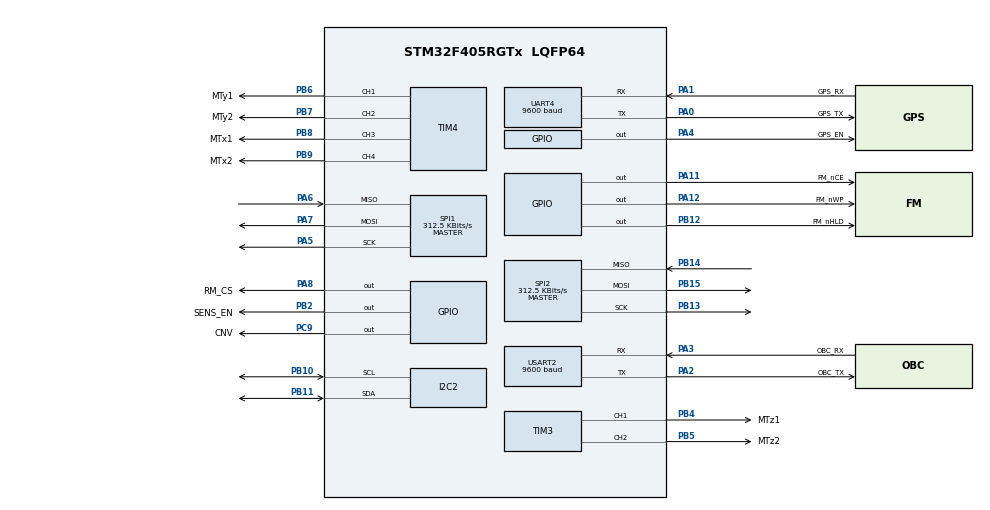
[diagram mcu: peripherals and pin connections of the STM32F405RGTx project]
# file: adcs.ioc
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Dma.Request0=USART2_TX
Dma.USART2_TX.0.Direction=DMA_MEMORY_TO_PERIPH
Dma.USART2_TX.0.FIFOMode=DMA_FIFOMODE_DISABLE
Dma.USART2_TX.0.Instance=DMA1_Stream6
Dma.USART2_TX.0.MemDataAlignment=DMA_MDATAALIGN_BYTE
Dma.USART2_TX.0.MemInc=DMA_MINC_ENABLE
Dma.USART2_TX.0.Mode=DMA_NORMAL
Dma.USART2_TX.0.PeriphDataAlignment=DMA_PDATAALIGN_BYTE
Dma.USART2_TX.0.PeriphInc=DMA_PINC_DISABLE
Dma.USART2_TX.0.Priority=DMA_PRIORITY_LOW
IWDG.Prescaler=IWDG_PRESCALER_256
IWDG.Reload=300
Mcu.Family=STM32F4
Mcu.Name=STM32F405RGTx
Mcu.Package=LQFP64
NVIC.DMA1_Stream6_IRQn=true\:0\:0\:false\:false\:true
NVIC.I2C2_EV_IRQn=true\:0\:0\:false\:false\:true
NVIC.PriorityGroup=NVIC_PRIORITYGROUP_4
NVIC.RTC_Alarm_IRQn=true\:0\:0\:false\:false\:true
NVIC.SPI1_IRQn=true\:0\:0\:false\:false\:true
NVIC.SPI2_IRQn=true\:0\:0\:false\:false\:true
NVIC.TIM7_IRQn=true\:0\:0\:false\:false\:true
NVIC.UART4_IRQn=true\:0\:0\:false\:false\:true
NVIC.USART2_IRQn=true\:0\:0\:false\:false\:true
PA0-WKUP.GPIO_Label=GPS_TX
PA0-WKUP.GPIO_Speed=GPIO_SPEED_FREQ_HIGH
PA0-WKUP.Mode=Asynchronous
PA0-WKUP.Signal=UART4_TX
PA1.GPIO_Label=GPS_RX
PA1.GPIO_Speed=GPIO_SPEED_FREQ_HIGH
PA1.Mode=Asynchronous
PA1.Signal=UART4_RX
PA11.GPIO_Label=FM_nCE
PA11.Signal=GPIO_Output
PA12.GPIO_Label=FM_nWP
PA12.Signal=GPIO_Output
PA13.Mode=Trace_Asynchronous_SW
PA13.Signal=SYS_JTMS-SWDIO
PA14.Mode=Trace_Asynchronous_SW
PA14.Signal=SYS_JTCK-SWCLK
PA2.GPIO_Label=OBC_TX
PA2.GPIO_Speed=GPIO_SPEED_FREQ_HIGH
PA2.Mode=Asynchronous
PA2.Signal=USART2_TX
PA3.GPIO_Label=OBC_RX
PA3.GPIO_Speed=GPIO_SPEED_FREQ_HIGH
PA3.Mode=Asynchronous
PA3.Signal=USART2_RX
PA4.GPIO_Label=GPS_EN
PA4.PinState=GPIO_PIN_SET
PA4.Signal=GPIO_Output
PA5.GPIO_Speed=GPIO_SPEED_FREQ_LOW
PA5.Mode=Full_Duplex_Master
PA5.Signal=SPI1_SCK
PA6.GPIO_Speed=GPIO_SPEED_FREQ_LOW
PA6.Mode=Full_Duplex_Master
PA6.Signal=SPI1_MISO
PA7.GPIO_Speed=GPIO_SPEED_FREQ_LOW
PA7.Mode=Full_Duplex_Master
PA7.Signal=SPI1_MOSI
PA8.GPIO_Label=RM_CS
PA8.Signal=GPIO_Output
PB10.GPIO_PuPdOD=GPIO_NOPULL
PB10.GPIO_Speed=GPIO_SPEED_FREQ_LOW
PB10.Mode=I2C
PB10.Signal=I2C2_SCL
PB11.GPIO_PuPdOD=GPIO_NOPULL
PB11.GPIO_Speed=GPIO_SPEED_FREQ_LOW
PB11.Mode=I2C
PB11.Signal=I2C2_SDA
PB12.GPIO_Label=FM_nHLD
PB12.Signal=GPIO_Output
PB13.GPIO_Speed=GPIO_SPEED_FREQ_LOW
PB13.Mode=Full_Duplex_Master
PB13.Signal=SPI2_SCK
PB14.GPIO_Speed=GPIO_SPEED_FREQ_LOW
PB14.Mode=Full_Duplex_Master
PB14.Signal=SPI2_MISO
PB15.GPIO_Speed=GPIO_SPEED_FREQ_LOW
PB15.Mode=Full_Duplex_Master
PB15.Signal=SPI2_MOSI
PB2.GPIO_Label=SENS_EN
PB2.PinState=GPIO_PIN_SET
PB2.Signal=GPIO_Output
PB3.Mode=Trace_Asynchronous_SW
PB3.Signal=SYS_JTDO-SWO
PB4.GPIO_Label=MTz1
PB4.Signal=S_TIM3_CH1
PB5.GPIO_Label=MTz2
PB5.Signal=S_TIM3_CH2
PB6.GPIO_Label=MTy1
PB6.Signal=S_TIM4_CH1
PB7.GPIO_Label=MTy2
PB7.Signal=S_TIM4_CH2
PB8.GPIO_Label=MTx1
PB8.Signal=S_TIM4_CH3
PB9.GPIO_Label=MTx2
PB9.Signal=S_TIM4_CH4
PC14-OSC32_IN.Mode=LSE-External-Oscillator
PC14-OSC32_IN.Signal=RCC_OSC32_IN
PC15-OSC32_OUT.Mode=LSE-External-Oscillator
PC15-OSC32_OUT.Signal=RCC_OSC32_OUT
PC9.GPIO_Label=CNV
PC9.Signal=GPIO_Output
PH0-OSC_IN.Mode=HSE-External-Oscillator
PH0-OSC_IN.Signal=RCC_OSC_IN
PH1-OSC_OUT.Mode=HSE-External-Oscillator
PH1-OSC_OUT.Signal=RCC_OSC_OUT
ProjectManager.HeapSize=0x200
ProjectManager.StackSize=0x400
ProjectManager.TargetToolchain=SW4STM32
RCC.48MHZClocksFreq_Value=22857142.85714286
RCC.AHBFreq_Value=80000000
RCC.APB1CLKDivider=RCC_HCLK_DIV2
RCC.APB1Freq_Value=40000000
RCC.APB1TimFreq_Value=80000000
RCC.APB2CLKDivider=RCC_HCLK_DIV2
RCC.APB2Freq_Value=40000000
RCC.APB2TimFreq_Value=80000000
RCC.CortexFreq_Value=80000000
RCC.HCLKFreq_Value=80000000
RCC.HSE_VALUE=12000000
RCC.HSI_VALUE=16000000
RCC.PLLM=6
RCC.PLLN=80
RCC.PLLQ=7
RCC.PLLSourceVirtual=RCC_PLLSOURCE_HSE
RCC.RCC_RTC_Clock_SourceVirtual=RCC_RTCCLKSOURCE_LSE
RCC.RCC_RTC_Clock_Source_FROM_HSE=RCC_RTCCLKSOURCE_HSE_DIV12
RCC.SYSCLKFreq_VALUE=80000000
RCC.SYSCLKSource=RCC_SYSCLKSOURCE_PLLCLK
RCC.VCOOutputFreq_Value=160000000
RTC.AlarmMask=RTC_ALARMMASK_DATEWEEKDAY
RTC.Format=RTC_FORMAT_BIN
SH.S_TIM3_CH1.0=TIM3_CH1,PWM Generation1 CH1
SH.S_TIM3_CH2.0=TIM3_CH2,PWM Generation2 CH2
SH.S_TIM4_CH1.0=TIM4_CH1,PWM Generation1 CH1
SH.S_TIM4_CH2.0=TIM4_CH2,PWM Generation2 CH2
SH.S_TIM4_CH3.0=TIM4_CH3,PWM Generation3 CH3
SH.S_TIM4_CH4.0=TIM4_CH4,PWM Generation4 CH4
SPI1.BaudRatePrescaler=SPI_BAUDRATEPRESCALER_128
SPI1.CalculateBaudRate=312.5 KBits/s
SPI1.Mode=SPI_MODE_MASTER
SPI2.BaudRatePrescaler=SPI_BAUDRATEPRESCALER_128
SPI2.CalculateBaudRate=312.5 KBits/s
SPI2.Mode=SPI_MODE_MASTER
TIM3.Channel-PWM\ Generation2\ CH2=TIM_CHANNEL_2
TIM4.Channel-PWM\ Generation2\ CH2=TIM_CHANNEL_2
TIM4.Channel-PWM\ Generation3\ CH3=TIM_CHANNEL_3
TIM4.Channel-PWM\ Generation4\ CH4=TIM_CHANNEL_4
TIM7.Period=50000
TIM7.Prescaler=2048
UART4.BaudRate=9600
USART2.BaudRate=9600
VP_CRC_VS_CRC.Mode=CRC_Activate
VP_IWDG_VS_IWDG.Mode=IWDG_Activate
VP_RTC_VS_RTC_Alarm_A_Intern.Mode=Alarm A
VP_TIM7_VS_ClockSourceINT.Mode=Enable_Timer
board=adcs

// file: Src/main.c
/**
 ******************************************************************************
 * File Name          : main.c
 * Description        : Main program body
 ******************************************************************************
 *
 * COPYRIGHT(c) 2016 STMicroelectronics
 *
 * Redistribution and use in source and binary forms, with or without modification,
 * are permitted provided that the following conditions are met:
 *   1. Redistributions of source code must retain the above copyright notice,
 *      this list of conditions and the following disclaimer.
 *   2. Redistributions in binary form must reproduce the above copyright notice,
 *      this list of conditions and the following disclaimer in the documentation
 *      and/or other materials provided with the distribution.
 *   3. Neither the name of STMicroelectronics nor the names of its contributors
 *      may be used to endorse or promote products derived from this software
 *      without specific prior written permission.
 *
 * THIS SOFTWARE IS PROVIDED BY THE COPYRIGHT HOLDERS AND CONTRIBUTORS "AS IS"
 * AND ANY EXPRESS OR IMPLIED WARRANTIES, INCLUDING, BUT NOT LIMITED TO, THE
 * IMPLIED WARRANTIES OF MERCHANTABILITY AND FITNESS FOR A PARTICULAR PURPOSE ARE
 * DISCLAIMED. IN NO EVENT SHALL THE COPYRIGHT HOLDER OR CONTRIBUTORS BE LIABLE
 * FOR ANY DIRECT, INDIRECT, INCIDENTAL, SPECIAL, EXEMPLARY, OR CONSEQUENTIAL
 * DAMAGES (INCLUDING, BUT NOT LIMITED TO, PROCUREMENT OF SUBSTITUTE GOODS OR
 * SERVICES; LOSS OF USE, DATA, OR PROFITS; OR BUSINESS INTERRUPTION) HOWEVER
 * CAUSED AND ON ANY THEORY OF LIABILITY, WHETHER IN CONTRACT, STRICT LIABILITY,
 * OR TORT (INCLUDING NEGLIGENCE OR OTHERWISE) ARISING IN ANY WAY OUT OF THE USE
 * OF THIS SOFTWARE, EVEN IF ADVISED OF THE POSSIBILITY OF SUCH DAMAGE.
 *
 ******************************************************************************
 */
#include "stm32f4xx_hal.h"

/* USER CODE BEGIN Includes */

#include "adcs_manager.h"

#include "sysview.h"

/* USER CODE END Includes */

CRC_HandleTypeDef hcrc;

I2C_HandleTypeDef hi2c2;

IWDG_HandleTypeDef hiwdg;

RTC_HandleTypeDef hrtc;

SPI_HandleTypeDef hspi1;
SPI_HandleTypeDef hspi2;

TIM_HandleTypeDef htim3;
TIM_HandleTypeDef htim4;
TIM_HandleTypeDef htim7;

UART_HandleTypeDef huart4;
UART_HandleTypeDef huart2;
DMA_HandleTypeDef hdma_usart2_tx;

/* USER CODE BEGIN PV */
/* Private variables ---------------------------------------------------------*/

/* USER CODE END PV */

void SystemClock_Config(void);
void Error_Handler(void);
static void MX_GPIO_Init(void);
static void MX_DMA_Init(void);
static void MX_I2C2_Init(void);
static void MX_SPI1_Init(void);
static void MX_SPI2_Init(void);
static void MX_TIM3_Init(void);
static void MX_TIM4_Init(void);
static void MX_UART4_Init(void);
static void MX_USART2_UART_Init(void);
static void MX_TIM7_Init(void);
static void MX_CRC_Init(void);
static void MX_IWDG_Init(void);
static void MX_RTC_Init(void);

void HAL_TIM_MspPostInit(TIM_HandleTypeDef *htim);

/* USER CODE BEGIN PFP */
/* Private function prototypes -----------------------------------------------*/

void adcs_sysview_print();

/* USER CODE END PFP */

int main(void) {

    /* USER CODE BEGIN 1 */

    uint32_t obc_request_time = 0;

    /* Reset error status */
    error_status = ERROR_OK;

    /* USER CODE END 1 */

    /* MCU Configuration----------------------------------------------------------*/

    /* Reset of all peripherals, Initializes the Flash interface and the Systick. */
    HAL_Init();

    /* Wait for EPS ready */
    HAL_Delay(EPS_DELAY_READY);

    /* Configure the system clock */
    SystemClock_Config();

    /* Initialize all configured peripherals */
    MX_GPIO_Init();
    MX_DMA_Init();
    MX_I2C2_Init();
    MX_SPI1_Init();
    MX_SPI2_Init();
    MX_TIM3_Init();
    MX_TIM4_Init();
    MX_UART4_Init();
    MX_USART2_UART_Init();
    MX_TIM7_Init();
    MX_CRC_Init();
    MX_IWDG_Init();
    MX_RTC_Init();

    /* USER CODE BEGIN 2 */

    SEGGER_SYSVIEW_Conf();
    sysview_init();

    HAL_IWDG_Refresh(&hiwdg);

    error_status = init_mem();
    error_status = increment_boot_counter();
    error_status = init_obc_communication(adcs_boot_cnt);

    get_time_UTC(&adcs_time.utc);
    error_status = init_gps(adcs_time.utc, &gps_state);
    error_status = init_tle();

    HAL_IWDG_Refresh(&hiwdg);

    error_status = init_actuators();
    error_status = init_measured_vectors();
    error_status = init_attitude_determination();

    /* Kick timer interrupt for timed threads */
    if (kick_TIM7_timed_interrupt(LOOP_TIME_TICKS) == HAL_ERROR) {
        ADCS_event_period_status = TIMED_EVENT_NOT_SERVICED;
    }
    HAL_IWDG_Refresh(&hiwdg);
    /* USER CODE END 2 */

    /**************************************/
//    adcs_time.utc.year = 16;
//    adcs_time.utc.month = 8;
//    adcs_time.utc.day = 8;
//    adcs_time.utc.weekday = RTC_WEEKDAY_MONDAY;
//    adcs_time.utc.hour = 20;
//    adcs_time.utc.min = 30;
//    adcs_time.utc.sec = 0;
//    set_time_UTC(adcs_time.utc);
//
//    int16_t XM[3000];
//    int32_t RM[3000];
//    uint16_t j = 0;
    /**************************************/

    /* Infinite loop */
    /* USER CODE BEGIN WHILE */
    while (1) {
        /* GPS update */
        error_status = update_gps(&gps_state);

        /* Control loop runs at 68ms, interrupt runs every ~1.2s, WDG at ~2.4s */
        if (ADCS_event_period_status == TIMED_EVENT_NOT_SERVICED) {
            /* Send to EPS a packet */
            update_eps_pkt();
            /* Close Magneto-torquer for ms */
            magneto_torquer_off();
            /* Update measured vectors */
            error_status = update_measured_vectors();
            /**************************************/
//                    if (j<3000) {
//                        RM[j] = adcs_sensors.mgn.rm_raw[0];
//                        XM[j] = adcs_sensors.imu.xm_raw[0];
//                        j++;
//                        RM[j] = adcs_sensors.mgn.rm_raw[1];
//                        XM[j] = adcs_sensors.imu.xm_raw[1];
//                        j++;
//                        RM[j] = adcs_sensors.mgn.rm_raw[2];
//                        XM[j] = adcs_sensors.imu.xm_raw[2];
//                        j++;
//
//                    } else {
//                        break;
//                    }
            /**************************************/
            /* Open Magneto-torquer with previous current values */
            magneto_torquer_on();
            /* Get time for RTC*/
            get_time_UTC(&adcs_time.utc);
            /* Check if time is correct */
            if (adcs_time.utc.year > 15) {
                /* When set time with OBC RTC update GPS_ALARM only in the first time*/
                if (adcs_time.set_time == false) {
                    update_gps_alarm_from_flash(adcs_time.utc, &gps_state);
                    obc_request_time = 0;
                    adcs_time.set_time = true;
                }
                /* Calculate decimal year and Julian day */
                error_status = time_converter();
                /* Check if the SGP4 is correct */
                if (update_sgp4() == ERROR_OK) {
                    /* Update reference vectors */
                    error_status = update_reference_vectors();
                    /* Calculate Euler angles and angular velocities */
                    error_status = update_attitude_determination();
                } else {
                    error_status = ERROR_SGP4;
                }
            } else {
                /* Time isn't set by OBC, request time every ~11sec */
                error_status = ERROR_TIME;
                adcs_time.set_time = false;
                uint32_t obc_request_get_tick = HAL_sys_GetTick();
                if (obc_request_get_tick - obc_request_time> OBC_REQUEST_TIME_UPDATE) {
                    time_management_request_time_in_utc(OBC_APP_ID);
                    obc_request_time = obc_request_get_tick;
                }
            }
            /* Calculate control signals */
            error_status = attitude_control();
            /* Set actuators according to control signals */
            error_status = update_actuators();
            /* Update flag */
            ADCS_event_period_status = TIMED_EVENT_SERVICED;
            /* Software error handler runs for actuator and sensor 230ms*/
            adcs_sysview_print();
            error_handler(error_status);
            error_status = ERROR_OK;
        }

        error_status = update_obc_communication();

        /* USER CODE END WHILE */

    }

}

/** System Clock Configuration
 */
void SystemClock_Config(void) {

    RCC_OscInitTypeDef RCC_OscInitStruct;
    RCC_ClkInitTypeDef RCC_ClkInitStruct;
    RCC_PeriphCLKInitTypeDef PeriphClkInitStruct;

    __HAL_RCC_PWR_CLK_ENABLE();

    __HAL_PWR_VOLTAGESCALING_CONFIG(PWR_REGULATOR_VOLTAGE_SCALE1);

    RCC_OscInitStruct.OscillatorType = RCC_OSCILLATORTYPE_LSI
            | RCC_OSCILLATORTYPE_HSE | RCC_OSCILLATORTYPE_LSE;
    RCC_OscInitStruct.HSEState = RCC_HSE_ON;
    RCC_OscInitStruct.LSEState = RCC_LSE_ON;
    RCC_OscInitStruct.LSIState = RCC_LSI_ON;
    RCC_OscInitStruct.PLL.PLLState = RCC_PLL_ON;
    RCC_OscInitStruct.PLL.PLLSource = RCC_PLLSOURCE_HSE;
    RCC_OscInitStruct.PLL.PLLM = 6;
    RCC_OscInitStruct.PLL.PLLN = 168;
    RCC_OscInitStruct.PLL.PLLP = RCC_PLLP_DIV2;
    RCC_OscInitStruct.PLL.PLLQ = 7;
    if (HAL_RCC_OscConfig(&RCC_OscInitStruct) != HAL_OK) {
        Error_Handler();
    }

    RCC_ClkInitStruct.ClockType = RCC_CLOCKTYPE_HCLK | RCC_CLOCKTYPE_SYSCLK
            | RCC_CLOCKTYPE_PCLK1 | RCC_CLOCKTYPE_PCLK2;
    RCC_ClkInitStruct.SYSCLKSource = RCC_SYSCLKSOURCE_PLLCLK;
    RCC_ClkInitStruct.AHBCLKDivider = RCC_SYSCLK_DIV1;
    RCC_ClkInitStruct.APB1CLKDivider = RCC_HCLK_DIV4;
    RCC_ClkInitStruct.APB2CLKDivider = RCC_HCLK_DIV2;
    if (HAL_RCC_ClockConfig(&RCC_ClkInitStruct, FLASH_LATENCY_5) != HAL_OK) {
        Error_Handler();
    }

    PeriphClkInitStruct.PeriphClockSelection = RCC_PERIPHCLK_RTC;
    PeriphClkInitStruct.RTCClockSelection = RCC_RTCCLKSOURCE_LSE;
    if (HAL_RCCEx_PeriphCLKConfig(&PeriphClkInitStruct) != HAL_OK) {
        Error_Handler();
    }

    HAL_SYSTICK_Config(HAL_RCC_GetHCLKFreq() / 1000);

    HAL_SYSTICK_CLKSourceConfig(SYSTICK_CLKSOURCE_HCLK);

    /* SysTick_IRQn interrupt configuration */
    HAL_NVIC_SetPriority(SysTick_IRQn, 0, 0);
}

/* CRC init function */
static void MX_CRC_Init(void) {

    hcrc.Instance = CRC;
    if (HAL_CRC_Init(&hcrc) != HAL_OK) {
        Error_Handler();
    }

}

/* I2C2 init function */
static void MX_I2C2_Init(void) {

    hi2c2.Instance = I2C2;
    hi2c2.Init.ClockSpeed = 100000;
    hi2c2.Init.DutyCycle = I2C_DUTYCYCLE_2;
    hi2c2.Init.OwnAddress1 = 0;
    hi2c2.Init.AddressingMode = I2C_ADDRESSINGMODE_7BIT;
    hi2c2.Init.DualAddressMode = I2C_DUALADDRESS_DISABLE;
    hi2c2.Init.OwnAddress2 = 0;
    hi2c2.Init.GeneralCallMode = I2C_GENERALCALL_DISABLE;
    hi2c2.Init.NoStretchMode = I2C_NOSTRETCH_ENABLE;
    if (HAL_I2C_Init(&hi2c2) != HAL_OK) {
        Error_Handler();
    }

}

/* IWDG init function */
static void MX_IWDG_Init(void) {

    hiwdg.Instance = IWDG;
    hiwdg.Init.Prescaler = IWDG_PRESCALER_256;
    hiwdg.Init.Reload = 300;
    if (HAL_IWDG_Init(&hiwdg) != HAL_OK) {
        Error_Handler();
    }

}

/* RTC init function */
static void MX_RTC_Init(void) {

    RTC_TimeTypeDef sTime;
    RTC_DateTypeDef sDate;
    RTC_AlarmTypeDef sAlarm;

    /**Initialize RTC and set the Time and Date
     */
    hrtc.Instance = RTC;
    hrtc.Init.HourFormat = RTC_HOURFORMAT_24;
    hrtc.Init.AsynchPrediv = 127;
    hrtc.Init.SynchPrediv = 255;
    hrtc.Init.OutPut = RTC_OUTPUT_DISABLE;
    hrtc.Init.OutPutPolarity = RTC_OUTPUT_POLARITY_HIGH;
    hrtc.Init.OutPutType = RTC_OUTPUT_TYPE_OPENDRAIN;
    if (HAL_RTC_Init(&hrtc) != HAL_OK) {
        Error_Handler();
    }

    sTime.Hours = 0;
    sTime.Minutes = 0;
    sTime.Seconds = 0;
    sTime.DayLightSaving = RTC_DAYLIGHTSAVING_NONE;
    sTime.StoreOperation = RTC_STOREOPERATION_RESET;
    if (HAL_RTC_SetTime(&hrtc, &sTime, RTC_FORMAT_BIN) != HAL_OK) {
        Error_Handler();
    }

    sDate.WeekDay = RTC_WEEKDAY_MONDAY;
    sDate.Month = RTC_MONTH_JANUARY;
    sDate.Date = 1;
    sDate.Year = 0;

    if (HAL_RTC_SetDate(&hrtc, &sDate, RTC_FORMAT_BIN) != HAL_OK) {
        Error_Handler();
    }

    /**Enable the Alarm A
     */
    sAlarm.AlarmTime.Hours = 0;
    sAlarm.AlarmTime.Minutes = 0;
    sAlarm.AlarmTime.Seconds = 0;
    sAlarm.AlarmTime.SubSeconds = 0;
    sAlarm.AlarmTime.DayLightSaving = RTC_DAYLIGHTSAVING_NONE;
    sAlarm.AlarmTime.StoreOperation = RTC_STOREOPERATION_RESET;
    sAlarm.AlarmMask = RTC_ALARMMASK_DATEWEEKDAY;
    sAlarm.AlarmSubSecondMask = RTC_ALARMSUBSECONDMASK_ALL;
    sAlarm.AlarmDateWeekDaySel = RTC_ALARMDATEWEEKDAYSEL_DATE;
    sAlarm.AlarmDateWeekDay = 1;
    sAlarm.Alarm = RTC_ALARM_A;
    if (HAL_RTC_SetAlarm_IT(&hrtc, &sAlarm, RTC_FORMAT_BIN) != HAL_OK) {
        Error_Handler();
    }

}

/* SPI1 init function */
static void MX_SPI1_Init(void) {

    hspi1.Instance = SPI1;
    hspi1.Init.Mode = SPI_MODE_MASTER;
    hspi1.Init.Direction = SPI_DIRECTION_2LINES;
    hspi1.Init.DataSize = SPI_DATASIZE_8BIT;
    hspi1.Init.CLKPolarity = SPI_POLARITY_LOW;
    hspi1.Init.CLKPhase = SPI_PHASE_1EDGE;
    hspi1.Init.NSS = SPI_NSS_SOFT;
    hspi1.Init.BaudRatePrescaler = SPI_BAUDRATEPRESCALER_256;
    hspi1.Init.FirstBit = SPI_FIRSTBIT_MSB;
    hspi1.Init.TIMode = SPI_TIMODE_DISABLE;
    hspi1.Init.CRCCalculation = SPI_CRCCALCULATION_DISABLE;
    hspi1.Init.CRCPolynomial = 10;
    if (HAL_SPI_Init(&hspi1) != HAL_OK) {
        Error_Handler();
    }

}

/* SPI2 init function */
static void MX_SPI2_Init(void) {

    hspi2.Instance = SPI2;
    hspi2.Init.Mode = SPI_MODE_MASTER;
    hspi2.Init.Direction = SPI_DIRECTION_2LINES;
    hspi2.Init.DataSize = SPI_DATASIZE_8BIT;
    hspi2.Init.CLKPolarity = SPI_POLARITY_LOW;
    hspi2.Init.CLKPhase = SPI_PHASE_1EDGE;
    hspi2.Init.NSS = SPI_NSS_SOFT;
    hspi2.Init.BaudRatePrescaler = SPI_BAUDRATEPRESCALER_128;
    hspi2.Init.FirstBit = SPI_FIRSTBIT_MSB;
    hspi2.Init.TIMode = SPI_TIMODE_DISABLE;
    hspi2.Init.CRCCalculation = SPI_CRCCALCULATION_DISABLE;
    hspi2.Init.CRCPolynomial = 10;
    if (HAL_SPI_Init(&hspi2) != HAL_OK) {
        Error_Handler();
    }

}

/* TIM3 init function */
static void MX_TIM3_Init(void) {

    TIM_MasterConfigTypeDef sMasterConfig;
    TIM_OC_InitTypeDef sConfigOC;

    htim3.Instance = TIM3;
    htim3.Init.Prescaler = 0;
    htim3.Init.CounterMode = TIM_COUNTERMODE_UP;
    htim3.Init.Period = 0;
    htim3.Init.ClockDivision = TIM_CLOCKDIVISION_DIV1;
    if (HAL_TIM_PWM_Init(&htim3) != HAL_OK) {
        Error_Handler();
    }

    sMasterConfig.MasterOutputTrigger = TIM_TRGO_RESET;
    sMasterConfig.MasterSlaveMode = TIM_MASTERSLAVEMODE_DISABLE;
    if (HAL_TIMEx_MasterConfigSynchronization(&htim3, &sMasterConfig)
            != HAL_OK) {
        Error_Handler();
    }

    sConfigOC.OCMode = TIM_OCMODE_PWM1;
    sConfigOC.Pulse = 0;
    sConfigOC.OCPolarity = TIM_OCPOLARITY_HIGH;
    sConfigOC.OCFastMode = TIM_OCFAST_DISABLE;
    if (HAL_TIM_PWM_ConfigChannel(&htim3, &sConfigOC, TIM_CHANNEL_1)
            != HAL_OK) {
        Error_Handler();
    }

    if (HAL_TIM_PWM_ConfigChannel(&htim3, &sConfigOC, TIM_CHANNEL_2)
            != HAL_OK) {
        Error_Handler();
    }

    HAL_TIM_MspPostInit(&htim3);

}

/* TIM4 init function */
static void MX_TIM4_Init(void) {

    TIM_MasterConfigTypeDef sMasterConfig;
    TIM_OC_InitTypeDef sConfigOC;

    htim4.Instance = TIM4;
    htim4.Init.Prescaler = 0;
    htim4.Init.CounterMode = TIM_COUNTERMODE_UP;
    htim4.Init.Period = 0;
    htim4.Init.ClockDivision = TIM_CLOCKDIVISION_DIV1;
    if (HAL_TIM_PWM_Init(&htim4) != HAL_OK) {
        Error_Handler();
    }

    sMasterConfig.MasterOutputTrigger = TIM_TRGO_RESET;
    sMasterConfig.MasterSlaveMode = TIM_MASTERSLAVEMODE_DISABLE;
    if (HAL_TIMEx_MasterConfigSynchronization(&htim4, &sMasterConfig)
            != HAL_OK) {
        Error_Handler();
    }

    sConfigOC.OCMode = TIM_OCMODE_PWM1;
    sConfigOC.Pulse = 0;
    sConfigOC.OCPolarity = TIM_OCPOLARITY_HIGH;
    sConfigOC.OCFastMode = TIM_OCFAST_DISABLE;
    if (HAL_TIM_PWM_ConfigChannel(&htim4, &sConfigOC, TIM_CHANNEL_1)
            != HAL_OK) {
        Error_Handler();
    }

    if (HAL_TIM_PWM_ConfigChannel(&htim4, &sConfigOC, TIM_CHANNEL_2)
            != HAL_OK) {
        Error_Handler();
    }

    if (HAL_TIM_PWM_ConfigChannel(&htim4, &sConfigOC, TIM_CHANNEL_3)
            != HAL_OK) {
        Error_Handler();
    }

    if (HAL_TIM_PWM_ConfigChannel(&htim4, &sConfigOC, TIM_CHANNEL_4)
            != HAL_OK) {
        Error_Handler();
    }

    HAL_TIM_MspPostInit(&htim4);

}

/* TIM7 init function */
static void MX_TIM7_Init(void) {

    TIM_MasterConfigTypeDef sMasterConfig;

    htim7.Instance = TIM7;
    htim7.Init.Prescaler = 2048;
    htim7.Init.CounterMode = TIM_COUNTERMODE_UP;
    htim7.Init.Period = 50000;
    if (HAL_TIM_Base_Init(&htim7) != HAL_OK) {
        Error_Handler();
    }

    sMasterConfig.MasterOutputTrigger = TIM_TRGO_RESET;
    sMasterConfig.MasterSlaveMode = TIM_MASTERSLAVEMODE_DISABLE;
    if (HAL_TIMEx_MasterConfigSynchronization(&htim7, &sMasterConfig)
            != HAL_OK) {
        Error_Handler();
    }

}

/* UART4 init function */
static void MX_UART4_Init(void) {

    huart4.Instance = UART4;
    huart4.Init.BaudRate = 9600;
    huart4.Init.WordLength = UART_WORDLENGTH_8B;
    huart4.Init.StopBits = UART_STOPBITS_1;
    huart4.Init.Parity = UART_PARITY_NONE;
    huart4.Init.Mode = UART_MODE_TX_RX;
    huart4.Init.HwFlowCtl = UART_HWCONTROL_NONE;
    huart4.Init.OverSampling = UART_OVERSAMPLING_16;
    if (HAL_UART_Init(&huart4) != HAL_OK) {
        Error_Handler();
    }

}

/* USART2 init function */
static void MX_USART2_UART_Init(void) {

    huart2.Instance = USART2;
    huart2.Init.BaudRate = 9600;
    huart2.Init.WordLength = UART_WORDLENGTH_8B;
    huart2.Init.StopBits = UART_STOPBITS_1;
    huart2.Init.Parity = UART_PARITY_NONE;
    huart2.Init.Mode = UART_MODE_TX_RX;
    huart2.Init.HwFlowCtl = UART_HWCONTROL_NONE;
    huart2.Init.OverSampling = UART_OVERSAMPLING_16;
    if (HAL_UART_Init(&huart2) != HAL_OK) {
        Error_Handler();
    }

}

static void MX_DMA_Init(void) {
    /* DMA controller clock enable */
    __HAL_RCC_DMA1_CLK_ENABLE();

    /* DMA interrupt init */
    /* DMA1_Stream6_IRQn interrupt configuration */
    HAL_NVIC_SetPriority(DMA1_Stream6_IRQn, 0, 0);
    HAL_NVIC_EnableIRQ(DMA1_Stream6_IRQn);

}

/** Configure pins as
 * Analog
 * Input
 * Output
 * EVENT_OUT
 * EXTI
 */
static void MX_GPIO_Init(void) {

    GPIO_InitTypeDef GPIO_InitStruct;

    /* GPIO Ports Clock Enable */
    __HAL_RCC_GPIOC_CLK_ENABLE();
    __HAL_RCC_GPIOH_CLK_ENABLE();
    __HAL_RCC_GPIOA_CLK_ENABLE();
    __HAL_RCC_GPIOB_CLK_ENABLE();

    /*Configure GPIO pin Output Level */
    HAL_GPIO_WritePin(GPS_EN_GPIO_Port, GPS_EN_Pin, GPIO_PIN_SET);

    /*Configure GPIO pin Output Level */
    HAL_GPIO_WritePin(SENS_EN_GPIO_Port, SENS_EN_Pin, GPIO_PIN_SET);

    /*Configure GPIO pin Output Level */
    HAL_GPIO_WritePin(FM_nHLD_GPIO_Port, FM_nHLD_Pin, GPIO_PIN_RESET);

    /*Configure GPIO pin Output Level */
    HAL_GPIO_WritePin(CNV_GPIO_Port, CNV_Pin, GPIO_PIN_RESET);

    /*Configure GPIO pin Output Level */
    HAL_GPIO_WritePin(GPIOA, RM_CS_Pin | FM_nCE_Pin | FM_nWP_Pin,
            GPIO_PIN_RESET);

    /*Configure GPIO pins : GPS_EN_Pin RM_CS_Pin FM_nCE_Pin FM_nWP_Pin */
    GPIO_InitStruct.Pin = GPS_EN_Pin | RM_CS_Pin | FM_nCE_Pin | FM_nWP_Pin;
    GPIO_InitStruct.Mode = GPIO_MODE_OUTPUT_PP;
    GPIO_InitStruct.Pull = GPIO_NOPULL;
    GPIO_InitStruct.Speed = GPIO_SPEED_FREQ_LOW;
    HAL_GPIO_Init(GPIOA, &GPIO_InitStruct);

    /*Configure GPIO pins : SENS_EN_Pin FM_nHLD_Pin */
    GPIO_InitStruct.Pin = SENS_EN_Pin | FM_nHLD_Pin;
    GPIO_InitStruct.Mode = GPIO_MODE_OUTPUT_PP;
    GPIO_InitStruct.Pull = GPIO_NOPULL;
    GPIO_InitStruct.Speed = GPIO_SPEED_FREQ_LOW;
    HAL_GPIO_Init(GPIOB, &GPIO_InitStruct);

    /*Configure GPIO pin : CNV_Pin */
    GPIO_InitStruct.Pin = CNV_Pin;
    GPIO_InitStruct.Mode = GPIO_MODE_OUTPUT_PP;
    GPIO_InitStruct.Pull = GPIO_NOPULL;
    GPIO_InitStruct.Speed = GPIO_SPEED_FREQ_LOW;
    HAL_GPIO_Init(CNV_GPIO_Port, &GPIO_InitStruct);

}

/* USER CODE BEGIN 4 */

void adcs_sysview_print() {
    SYSVIEW_PRINT("BOOT COUNTER %ld", adcs_boot_cnt);
    SYSVIEW_PRINT("ERROR STATUS %d", error_status);
    SYSVIEW_PRINT("GPS STATUS %d", gps_state.status);
    SYSVIEW_PRINT("EULER %.2f %.2f %.2f", DEG(WahbaRot.Euler[0]),
            DEG(WahbaRot.Euler[1]), DEG(WahbaRot.Euler[2]));
    SYSVIEW_PRINT("W %.2f %.2f %.2f", DEG(WahbaRot.W[0]), DEG(WahbaRot.W[1]),
            DEG(WahbaRot.W[2]));
    SYSVIEW_PRINT("TEMPERATURE %.2f", adcs_sensors.temp.temp_c);
    SYSVIEW_PRINT("IGRF %.2f %.2f %.2f %.2f", igrf_vector.Xm,
            igrf_vector.Ym, igrf_vector.Zm, igrf_vector.norm);
    SYSVIEW_PRINT("RM %.2f %.2f %.2f %.2f", adcs_sensors.mgn.rm_f[0],
            adcs_sensors.mgn.rm_f[1], adcs_sensors.mgn.rm_f[2], adcs_sensors.mgn.rm_norm);
    SYSVIEW_PRINT("XM %.2f %.2f %.2f %.2f", adcs_sensors.imu.xm_f[0],
            adcs_sensors.imu.xm_f[1], adcs_sensors.imu.xm_f[2], adcs_sensors.imu.xm_norm);
    SYSVIEW_PRINT("GYRO %.2f %.2f %.2f", DEG(adcs_sensors.imu.gyr_f[0]),
            DEG(adcs_sensors.imu.gyr_f[1]), DEG(adcs_sensors.imu.gyr_f[2]));
    SYSVIEW_PRINT("GYRO %d %d %d", adcs_sensors.imu.gyr_raw[0],
            adcs_sensors.imu.gyr_raw[1], adcs_sensors.imu.gyr_raw[2]);
    SYSVIEW_PRINT("V %.2f %.2f %.2f %.2f %.2f", adcs_sensors.sun.v_sun[0],
            adcs_sensors.sun.v_sun[1], adcs_sensors.sun.v_sun[2],
            adcs_sensors.sun.v_sun[3], adcs_sensors.sun.v_sun[4]);
    SYSVIEW_PRINT("SPIN RPM %ld", adcs_actuator.spin_torquer.m_RPM);
    SYSVIEW_PRINT("SPIN STATUS %d", adcs_actuator.spin_torquer.status);
    SYSVIEW_PRINT("ECI %.2f %.2f %.2f", p_eci.x, p_eci.y, p_eci.z);
    SYSVIEW_PRINT("CURRENTS %d %d", adcs_actuator.magneto_torquer.current_y,
            adcs_actuator.magneto_torquer.current_z);
    SYSVIEW_PRINT("SPIN RPM %ld", adcs_actuator.spin_torquer.RPM);
    SYSVIEW_PRINT("SP SPIN %.2f", control.sp_rpm);
}

/* USER CODE END 4 */

void Error_Handler(void) {
    /* USER CODE BEGIN Error_Handler */
    error_status = ERROR_HAL_INIT;
    /* User can add his own implementation to report the HAL error return state */
    while (1) {
        return;
    }
    /* USER CODE END Error_Handler */
}

/************************ (C) COPYRIGHT STMicroelectronics *****END OF FILE****/
